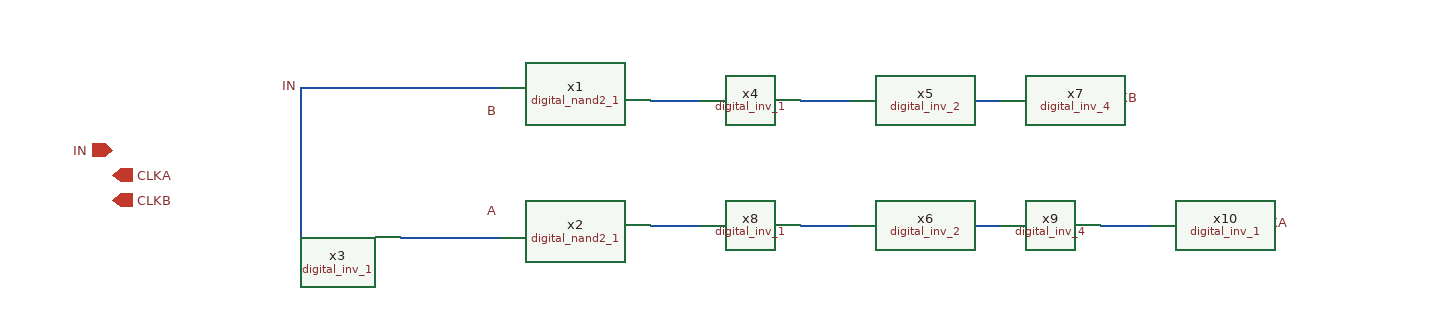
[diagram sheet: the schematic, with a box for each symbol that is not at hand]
v {xschem version=3.4.7 file_version=1.2}
G {}
K {}
V {}
S {}
E {}
N 370 -310 450 -310 {lab=IN}
N 370 -190 450 -190 {lab=#net1}
N 290 -310 290 -190 {lab=IN}
N 290 -310 370 -310 {lab=IN}
N 570 -300 610 -300 {lab=#net2}
N 570 -200 610 -200 {lab=#net3}
N 690 -300 730 -300 {lab=#net4}
N 690 -200 730 -200 {lab=#net5}
N 810 -300 850 -300 {lab=A}
N 810 -200 850 -200 {lab=B}
N 930 -200 970 -200 {lab=#net6}
C {lab_wire.sym} 450 -290 0 0 {name=p4 lab=B}
C {lab_wire.sym} 450 -210 0 0 {name=p8 lab=A}
C {lab_wire.sym} 930 -300 0 1 {name=p30 lab=CLKB}
C {lab_wire.sym} 810 -200 0 1 {name=p5 lab=B}
C {lab_wire.sym} 290 -310 0 0 {name=p13 lab=IN}
C {ipin.sym} 140 -260 0 0 {name=p18 lab=IN}
C {opin.sym} 140 -240 0 0 {name=p21 lab=CLKA}
C {opin.sym} 140 -220 0 0 {name=p22 lab=CLKB}
C {lab_wire.sym} 1050 -200 0 1 {name=p26 lab=CLKA}
C {lab_wire.sym} 810 -300 0 1 {name=p31 lab=A}
C {sscs-chipathon2025-LNA/designs/libs/core_analog/digital/digital_nand2_1.sym} 510 -300 0 0 {name=x1}
C {sscs-chipathon2025-LNA/designs/libs/core_analog/digital/digital_nand2_1.sym} 510 -200 0 0 {name=x2}
C {sscs-chipathon2025-LNA/designs/libs/core_analog/digital/digital_inv_1.sym} 330 -190 0 0 {name=x3}
C {sscs-chipathon2025-LNA/designs/libs/core_analog/digital/digital_inv_1.sym} 650 -300 0 0 {name=x4}
C {sscs-chipathon2025-LNA/designs/libs/core_analog/digital/digital_inv_1.sym} 650 -200 0 0 {name=x8}
C {sscs-chipathon2025-LNA/designs/libs/core_analog/digital/digital_inv_2.sym} 770 -300 0 0 {name=x5}
C {sscs-chipathon2025-LNA/designs/libs/core_analog/digital/digital_inv_2.sym} 770 -200 0 0 {name=x6}
C {sscs-chipathon2025-LNA/designs/libs/core_analog/digital/digital_inv_4.sym} 890 -300 0 0 {name=x7}
C {sscs-chipathon2025-LNA/designs/libs/core_analog/digital/digital_inv_4.sym} 890 -200 0 0 {name=x9}
C {sscs-chipathon2025-LNA/designs/libs/core_analog/digital/digital_inv_1.sym} 1010 -200 0 0 {name=x10}
